VERSION 5.8 ;
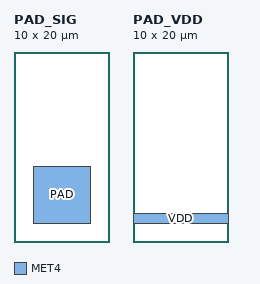
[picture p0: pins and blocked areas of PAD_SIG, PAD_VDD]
MACRO PAD_SIG
  CLASS PAD INOUT ;
  ORIGIN 0 0 ;
  SIZE 10 BY 20 ;
  SYMMETRY X Y R90 ;
  PIN PAD
    DIRECTION INOUT ;
    USE SIGNAL ;
    PORT
      LAYER MET4 ;
      RECT 2 2 8 8 ;
    END
  END PAD
END PAD_SIG
MACRO PAD_VDD
  CLASS PAD POWER ;
  SIZE 10 BY 20 ;
  PIN VDD
    DIRECTION INOUT ;
    USE POWER ;
    PORT
      LAYER MET4 ;
      RECT 0 2 10 3 ;
    END
  END VDD
END PAD_VDD
MACRO CORNER
  CLASS ENDCAP TOPLEFT ;
  SIZE 20 BY 20 ;
END CORNER
MACRO IO_FILL
  CLASS PAD SPACER ;
  SIZE 1 BY 20 ;
END IO_FILL
END LIBRARY
